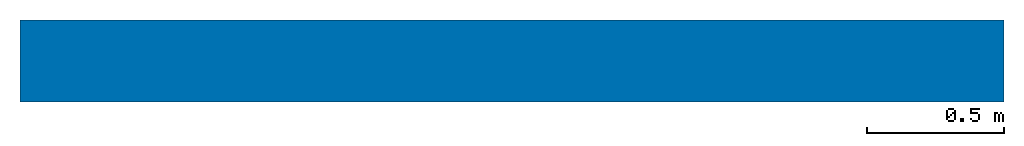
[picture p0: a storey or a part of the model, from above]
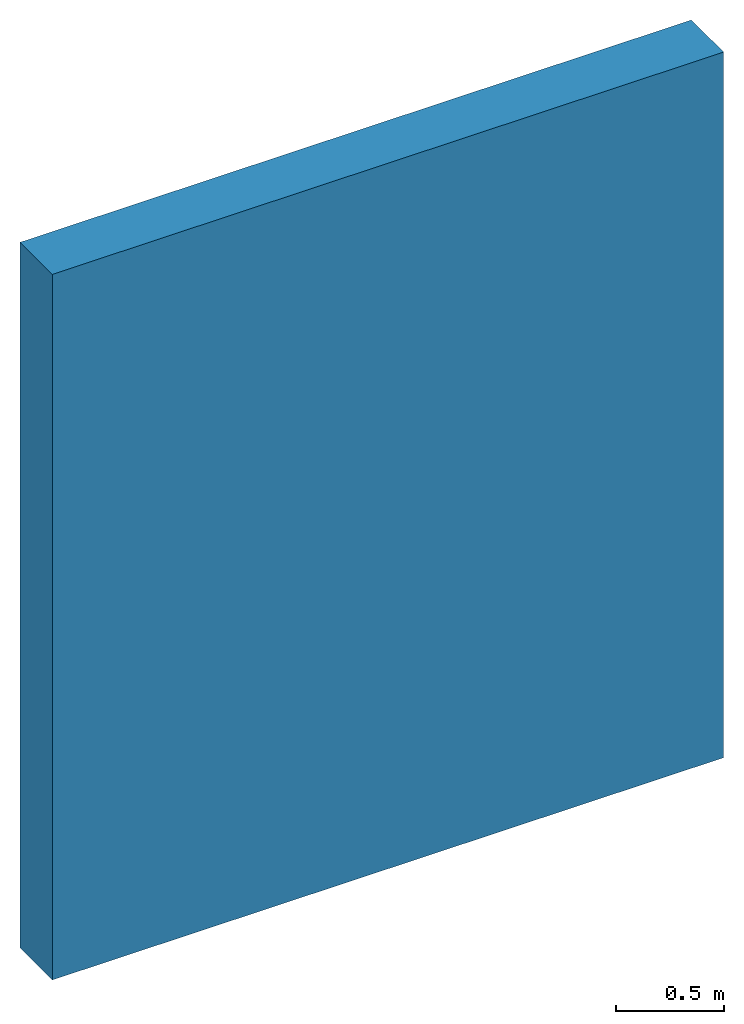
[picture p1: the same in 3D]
Properties of the parts of a building model (IFC2X3)

# File
Description: ViewDefinition [CoordinationView_V2.0]
File name: Project Number
Time: 2023-02-28T14:01:39
Written by: The EXPRESS Data Manager Version 5.02.0100.07 : 28 Aug 2013
Made in: 22.0.2.392 - Exporter 22.0.2.392 - Alternate UI 22.0.2.392
Comment: STEP Physical File produced by: The EXPRESS Data Manager Version 5.02.0100.07 : 28 Aug 2013 * Module: EDMstepFileFactory/EDMstandAlone * Creation date: Tue Feb 28 14:01:39 2023 * Host: DESKTOP-7JO305E * Database: C:\Users\User\AppData\Local\Temp\410f4ce6-7ac8-4cb9-9bff-3ffc1cf16495\75a33550-284a-41a0-9cee-35bcec03668a\ifc * Database version: 5507 * Database creation date: Tue Feb 28 14:01:34 2023 * Schema: IFC2X3 * Model: DataRepository.ifc * Model creation date: Tue Feb 28 14:01:35 2023 * Header model: DataRepository.ifc_HeaderModel * Header model creation date: Tue Feb 28 14:01:35 2023 * EDMuser: sdai-user * EDMgroup: sdai-group * License ID and type: 5605 : Permanent license. Expiry date: * EDMstepFileFactory options: 020000

# IfcProject, Project Number
LongName: Project Name; Phase: Project Status

# IfcSite, Default
RefLatitude: 51, 30, 23, 112487; RefLongitude: 0, -7, -37, -956022; RefElevation: 0 mm
Pset_ProductRequirements - Category: Project Information

# IfcBuilding
Pset_BuildingCommon - NumberOfStoreys: 1
Pset_ProductRequirements - Category: Project Information

# IfcBuildingStorey: Level:Circle Head - Project Datum, Level 0
LongName: Level 0; Elevation: 0 mm
Pset_AirSideSystemInformation - Name: Level 0
Pset_ProductRequirements - Name: Level 0; Category: Levels

# IfcWallStandardCase: Basic Wall:Wall-Fnd_300Con_Footing, Basic Wall:Wall-Fnd_300Con_Footing:318954
In: Level 0
Type - PredefinedType: STANDARD; Material: Concrete, Cast In Situ 300 mm
Type - Pset_ElementShading - Roughness: 914.4 mm
Type - Pset_ProductRequirements - Category: Walls
Type - Pset_WallCommon - ThermalTransmittance: 3.48667 kg/K/s3; IsExternal: yes
Pset_QuantityTakeOff - Reference: Wall-Fnd_300Con_Footing; sets with these values: 2
Pset_WallCommon - Reference: Wall-Fnd_300Con_Footing; ExtendToStructure: no; LoadBearing: no
